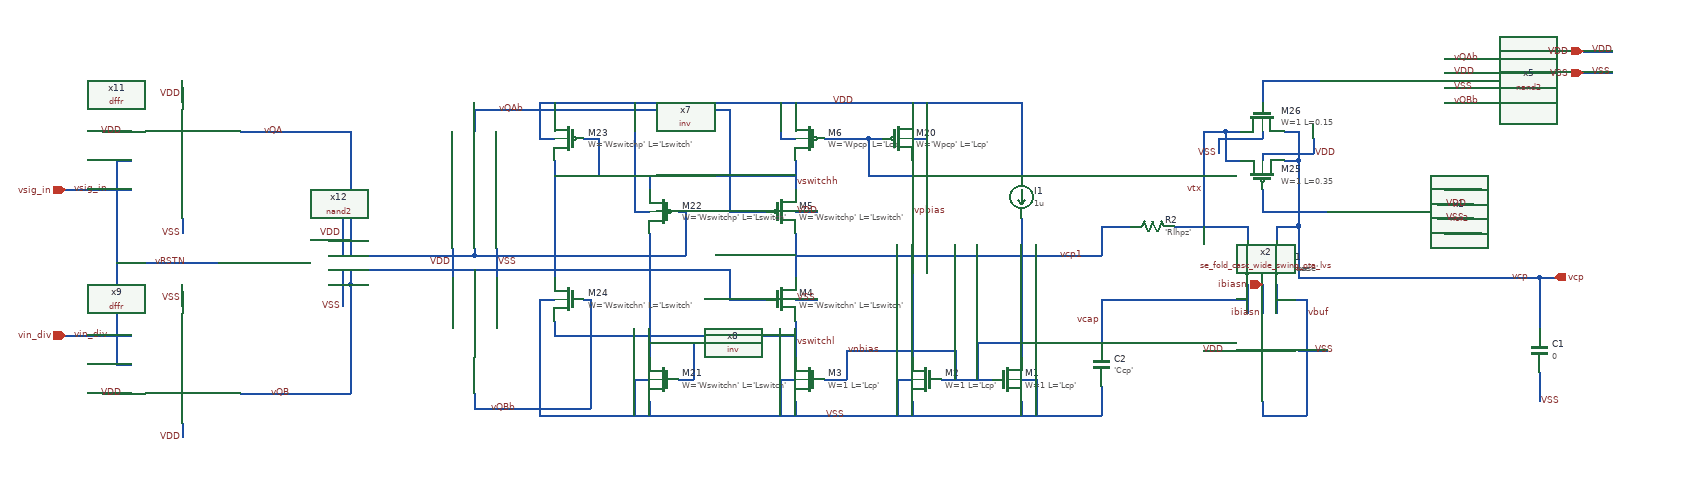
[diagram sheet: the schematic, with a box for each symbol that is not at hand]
v {xschem version=2.9.9 file_version=1.2 }
G {}
K {}
V {}
S {}
E {}
N -1440 -820 -1350 -820 { lab=vin_div}
N -1440 -1020 -1350 -1020 { lab=vsig_in}
N -1080 -890 -1050 -890 { lab=vQB}
N -280 -730 -280 -710 { lab=VSS}
N -300 -760 -280 -760 { lab=VSS}
N -300 -760 -300 -710 { lab=VSS}
N -280 -1090 -260 -1090 { lab=VDD}
N -280 -1140 -280 -1120 { lab=VDD}
N -260 -1140 -260 -1090 { lab=VDD}
N -240 -760 -170 -760 { lab=vnbias}
N -340 -1090 -340 -1040 { lab=vpbias}
N -340 -1040 -280 -1040 { lab=vpbias}
N -340 -1090 -320 -1090 { lab=vpbias}
N -280 -1060 -280 -790 { lab=vpbias}
N -130 -730 -130 -710 { lab=VSS}
N -130 -760 -110 -760 { lab=VSS}
N -110 -760 -110 -710 { lab=VSS}
N -400 -1090 -340 -1090 { lab=vpbias}
N -460 -1090 -440 -1090 { lab=VDD}
N -460 -1140 -460 -1090 { lab=VDD}
N -440 -1140 -440 -1120 { lab=VDD}
N -440 -730 -440 -710 { lab=VSS}
N -460 -760 -440 -760 { lab=VSS}
N -460 -760 -460 -710 { lab=VSS}
N -220 -800 -220 -760 { lab=vnbias}
N -370 -800 -220 -800 { lab=vnbias}
N -370 -800 -370 -760 { lab=vnbias}
N -400 -760 -370 -760 { lab=vnbias}
N -440 -1060 -440 -1020 { lab=vswitchh}
N -440 -960 -440 -900 { lab=vcp1}
N -440 -840 -440 -790 { lab=vswitchl}
N -440 -870 -410 -870 { lab=VSS}
N -440 -990 -410 -990 { lab=VDD}
N -130 -1140 -130 -1040 { lab=VDD}
N -130 -980 -130 -790 { lab=vnbias}
N -190 -810 -190 -760 { lab=vnbias}
N -190 -810 -130 -810 { lab=vnbias}
N 200 -710 260 -710 { lab=vbuf}
N 200 -730 200 -710 { lab=vbuf}
N -20 -750 -20 -710 { lab=VSS}
N 220 -870 260 -870 { lab=vbuf}
N 260 -870 260 -710 { lab=vbuf}
N -20 -870 -20 -810 { lab=vcap}
N 180 -890 180 -850 { lab=vcap}
N 220 -890 220 -850 { lab=vbuf}
N -440 -930 -20 -930 { lab=vcp1}
N 180 -970 180 -950 { lab=vtx}
N 220 -970 220 -950 { lab=vcp}
N -660 -990 -640 -990 { lab=VDD}
N -600 -760 -580 -760 { lab=#net1}
N -580 -810 -580 -760 { lab=#net1}
N -640 -810 -580 -810 { lab=#net1}
N -770 -840 -770 -820 { lab=vswitchl}
N -790 -870 -770 -870 { lab=VSS}
N -790 -1090 -770 -1090 { lab=VDD}
N -790 -1140 -790 -1090 { lab=VDD}
N -770 -1140 -770 -1120 { lab=VDD}
N -660 -760 -640 -760 { lab=VSS}
N -640 -730 -640 -710 { lab=VSS}
N -660 -760 -660 -710 { lab=VSS}
N -730 -1090 -710 -1090 { lab=#net2}
N -710 -1090 -710 -1040 { lab=#net2}
N -770 -1040 -710 -1040 { lab=#net2}
N -640 -1040 -440 -1040 { lab=vswitchh}
N -770 -820 -440 -820 { lab=vswitchl}
N -500 -990 -480 -990 { lab=vQAb}
N -600 -990 -590 -990 { lab=vQA}
N -500 -870 -480 -870 { lab=vQB}
N -730 -870 -720 -870 { lab=vQBb}
N -790 -710 -20 -710 { lab=VSS}
N -790 -1140 -130 -1140 { lab=VDD}
N -530 -990 -500 -990 { lab=vQAb}
N -530 -910 -530 -870 { lab=vQB}
N -530 -870 -500 -870 { lab=vQB}
N -640 -1040 -640 -1020 { lab=vswitchh}
N -640 -960 -640 -790 { lab=#net1}
N -660 -1140 -660 -990 { lab=VDD}
N -790 -870 -790 -710 { lab=VSS}
N -770 -1060 -770 -900 { lab=#net2}
N -20 -870 10 -870 { lab=vcap}
N 150 -1100 150 -1080 { lab=vtx}
N 150 -1100 170 -1100 { lab=vtx}
N 150 -1080 150 -1060 { lab=vtx}
N 150 -1060 170 -1060 { lab=vtx}
N 230 -1100 250 -1100 { lab=vcp}
N 250 -1100 250 -1060 { lab=vcp}
N 230 -1060 250 -1060 { lab=vcp}
N 110 -870 180 -870 { lab=vcap}
N 200 -1020 200 -990 { lab=#net3}
N 200 -1170 200 -1140 { lab=#net4}
N 200 -1070 200 -1060 { lab=VDD}
N 200 -1100 200 -1090 { lab=VSS}
N 200 -1070 270 -1070 { lab=VDD}
N 270 -1090 270 -1070 { lab=VDD}
N 140 -1090 200 -1090 { lab=VSS}
N 140 -1090 140 -1070 { lab=VSS}
N 120 -1100 150 -1100 { lab=vtx}
N 10 -870 110 -870 { lab=vcap}
N -20 -970 -20 -930 { lab=vcp1}
N 220 -970 250 -970 { lab=vcp}
N 200 -1170 280 -1170 { lab=#net4}
N 450 -1200 500 -1200 { lab=vQAb}
N 450 -1140 500 -1140 { lab=vQBb}
N 450 -1020 500 -1020 { lab=vQA}
N 450 -960 500 -960 { lab=vQB}
N 250 -970 250 -900 { lab=vcp}
N 250 -900 580 -900 { lab=vcp}
N -1200 -1100 -1050 -1100 { lab=vQA}
N -1200 -740 -1050 -740 { lab=vQB}
N -1370 -920 -1230 -920 { lab=vRSTN}
N -880 -1130 -880 -1100 { lab=vQAb}
N -880 -740 -880 -720 { lab=vQBb}
N -880 -940 -880 -930 { lab=vQA}
N -880 -910 -880 -900 { lab=vQB}
N -1050 -1100 -1050 -930 { lab=vQA}
N -1050 -930 -880 -930 { lab=vQA}
N -880 -1130 -530 -1130 { lab=vQAb}
N -530 -1130 -530 -990 { lab=vQAb}
N -880 -930 -590 -930 { lab=vQA}
N -590 -990 -590 -930 { lab=vQA}
N -1080 -950 -1050 -950 { lab=vQA}
N -1050 -910 -1050 -890 { lab=vQB}
N -1050 -910 -530 -910 { lab=vQB}
N -880 -720 -720 -720 { lab=vQBb}
N -720 -870 -720 -720 { lab=vQBb}
N -1370 -780 -1350 -780 { lab=vRSTN}
N -1370 -1060 -1370 -780 { lab=vRSTN}
N -1370 -1060 -1350 -1060 { lab=vRSTN}
N -1390 -1100 -1350 -1100 { lab=VDD}
N -1390 -740 -1350 -740 { lab=VDD}
N 580 -900 580 -830 { lab=vcp}
N -20 -970 20 -970 { lab=vcp1}
N 80 -970 180 -970 { lab=vtx}
N 120 -1100 120 -970 { lab=vtx}
N 250 -1060 250 -970 { lab=vcp}
N 200 -990 290 -990 { lab=#net3}
N -1050 -890 -1050 -740 { lab=vQB}
N 200 -890 200 -850 { lab=ibiasn}
N 120 -800 150 -800 { lab=VDD}
N 250 -800 290 -800 { lab=VSS}
N 580 -770 580 -730 { lab=VSS}
N 640 -1180 680 -1180 { lab=VSS}
N 640 -1210 680 -1210 { lab=VDD}
N 580 -900 600 -900 { lab=vcp}
N -910 -940 -910 -900 { lab=VDD}
N -850 -940 -850 -900 { lab=VSS}
N -1280 -1160 -1280 -1140 { lab=VDD}
N -1280 -980 -1280 -960 { lab=VSS}
N -1280 -880 -1280 -860 { lab=VSS}
N -1280 -700 -1280 -680 { lab=VDD}
N -1080 -930 -1060 -930 { lab=VDD}
N -1060 -980 -1060 -930 { lab=VDD}
N -1080 -910 -1060 -910 { lab=VSS}
N -1060 -910 -1060 -860 { lab=VSS}
N 450 -1180 490 -1180 { lab=VDD}
N 490 -1180 500 -1180 { lab=VDD}
N 450 -1160 490 -1160 { lab=VSS}
N 490 -1160 500 -1160 { lab=VSS}
N 440 -1000 480 -1000 { lab=VDD}
N 480 -1000 490 -1000 { lab=VDD}
N 440 -980 480 -980 { lab=#net5}
N 480 -980 490 -980 { lab=#net5}
C {devices/title.sym} 160 -30 0 0 {name=l1 author="Nikhil Poole"}
C {devices/lab_wire.sym} -1380 -1020 0 0 {name=l2 sig_type=std_logic lab=vsig_in}
C {devices/lab_wire.sym} -1380 -820 0 0 {name=l3 sig_type=std_logic lab=vin_div}
C {devices/lab_wire.sym} -370 -800 0 1 {name=l5 sig_type=std_logic lab=vnbias}
C {devices/lab_wire.sym} -280 -990 0 1 {name=l6 sig_type=std_logic lab=vpbias}
C {devices/isource.sym} -130 -1010 0 1 {name=I1 value=1u}
C {sky130_fd_pr/nfet_01v8.sym} -150 -760 0 0 {name=M1
L='Lcp'
W=1
nf=1 
mult=100
ad="'int((nf+1)/2) * W/nf * 0.29'" 
pd="'2*int((nf+1)/2) * (W/nf + 0.29)'"
as="'int((nf+2)/2) * W/nf * 0.29'" 
ps="'2*int((nf+2)/2) * (W/nf + 0.29)'"
nrd="'0.29 / W'" nrs="'0.29 / W'"
sa=0 sb=0 sd=0
model=nfet_01v8
spiceprefix=X
}
C {sky130_fd_pr/nfet_01v8.sym} -260 -760 0 1 {name=M2
L='Lcp'
W=1
nf=1 
mult=1
ad="'int((nf+1)/2) * W/nf * 0.29'" 
pd="'2*int((nf+1)/2) * (W/nf + 0.29)'"
as="'int((nf+2)/2) * W/nf * 0.29'" 
ps="'2*int((nf+2)/2) * (W/nf + 0.29)'"
nrd="'0.29 / W'" nrs="'0.29 / W'"
sa=0 sb=0 sd=0
model=nfet_01v8
spiceprefix=X
}
C {sky130_fd_pr/nfet_01v8.sym} -420 -760 0 1 {name=M3
L='Lcp'
W=1
nf=1 
mult=1
ad="'int((nf+1)/2) * W/nf * 0.29'" 
pd="'2*int((nf+1)/2) * (W/nf + 0.29)'"
as="'int((nf+2)/2) * W/nf * 0.29'" 
ps="'2*int((nf+2)/2) * (W/nf + 0.29)'"
nrd="'0.29 / W'" nrs="'0.29 / W'"
sa=0 sb=0 sd=0
model=nfet_01v8
spiceprefix=X
}
C {sky130_fd_pr/nfet_01v8_lvt.sym} -460 -870 0 0 {name=M4
L='Lswitch'
W='Wswitchn'
nf=1
mult=1
ad="'int((nf+1)/2) * W/nf * 0.29'" 
pd="'2*int((nf+1)/2) * (W/nf + 0.29)'"
as="'int((nf+2)/2) * W/nf * 0.29'" 
ps="'2*int((nf+2)/2) * (W/nf + 0.29)'"
nrd="'0.29 / W'" nrs="'0.29 / W'"
sa=0 sb=0 sd=0
model=nfet_01v8_lvt
spiceprefix=X
}
C {sky130_fd_pr/pfet_01v8_lvt.sym} -460 -990 0 0 {name=M5
L='Lswitch'
W='Wswitchp'
nf=1
mult=1
ad="'int((nf+1)/2) * W/nf * 0.29'" 
pd="'2*int((nf+1)/2) * (W/nf + 0.29)'"
as="'int((nf+2)/2) * W/nf * 0.29'" 
ps="'2*int((nf+2)/2) * (W/nf + 0.29)'"
nrd="'0.29 / W'" nrs="'0.29 / W'"
sa=0 sb=0 sd=0
model=pfet_01v8_lvt
spiceprefix=X
}
C {devices/lab_wire.sym} 540 -900 0 1 {name=l12 sig_type=std_logic lab=vcp}
C {sky130_fd_pr/pfet_01v8.sym} -420 -1090 0 1 {name=M6
L='Lcp'
W='Wpcp'
nf=1
mult='Mpcp'
ad="'int((nf+1)/2) * W/nf * 0.29'" 
pd="'2*int((nf+1)/2) * (W/nf + 0.29)'"
as="'int((nf+2)/2) * W/nf * 0.29'" 
ps="'2*int((nf+2)/2) * (W/nf + 0.29)'"
nrd="'0.29 / W'" nrs="'0.29 / W'"
sa=0 sb=0 sd=0
model=pfet_01v8
spiceprefix=X
}
C {sky130_fd_pr/pfet_01v8.sym} -300 -1090 0 0 {name=M20
L='Lcp'
W='Wpcp'
nf=1
mult='Mpcp'
ad="'int((nf+1)/2) * W/nf * 0.29'" 
pd="'2*int((nf+1)/2) * (W/nf + 0.29)'"
as="'int((nf+2)/2) * W/nf * 0.29'" 
ps="'2*int((nf+2)/2) * (W/nf + 0.29)'"
nrd="'0.29 / W'" nrs="'0.29 / W'"
sa=0 sb=0 sd=0
model=pfet_01v8
spiceprefix=X
}
C {devices/capa.sym} -20 -780 0 0 {name=C2
m=1
value='Ccp'
footprint=1206
device="ceramic capacitor"}
C {devices/res.sym} 220 -920 0 0 {name=R1
value='Rbase'
footprint=1206
device=resistor
m=1}
C {devices/res.sym} 180 -920 0 1 {name=R4
value='Kcap*Rbase'
footprint=1206
device=resistor
m=1}
C {devices/lab_wire.sym} -20 -840 0 0 {name=l35 sig_type=std_logic lab=vcap}
C {devices/lab_wire.sym} 260 -850 2 0 {name=l36 sig_type=std_logic lab=vbuf}
C {devices/lab_wire.sym} -1130 -740 0 0 {name=l37 sig_type=std_logic lab=vQB}
C {devices/lab_wire.sym} -440 -1030 0 1 {name=l38 sig_type=std_logic lab=vswitchh}
C {devices/lab_wire.sym} -440 -810 0 1 {name=l39 sig_type=std_logic lab=vswitchl}
C {sky130_fd_pr/nfet_01v8.sym} -620 -760 0 1 {name=M21
L='Lswitch'
W='Wswitchn'
nf=1 
mult=1
ad="'int((nf+1)/2) * W/nf * 0.29'" 
pd="'2*int((nf+1)/2) * (W/nf + 0.29)'"
as="'int((nf+2)/2) * W/nf * 0.29'" 
ps="'2*int((nf+2)/2) * (W/nf + 0.29)'"
nrd="'0.29 / W'" nrs="'0.29 / W'"
sa=0 sb=0 sd=0
model=nfet_01v8
spiceprefix=X
}
C {sky130_fd_pr/pfet_01v8.sym} -620 -990 0 1 {name=M22
L='Lswitch'
W='Wswitchp'
nf=1
mult=1
ad="'int((nf+1)/2) * W/nf * 0.29'" 
pd="'2*int((nf+1)/2) * (W/nf + 0.29)'"
as="'int((nf+2)/2) * W/nf * 0.29'" 
ps="'2*int((nf+2)/2) * (W/nf + 0.29)'"
nrd="'0.29 / W'" nrs="'0.29 / W'"
sa=0 sb=0 sd=0
model=pfet_01v8
spiceprefix=X
}
C {devices/lab_wire.sym} -1170 -1100 0 1 {name=l40 sig_type=std_logic lab=vQA}
C {sky130_fd_pr/pfet_01v8.sym} -750 -1090 0 1 {name=M23
L='Lswitch'
W='Wswitchp'
nf=1
mult=1
ad="'int((nf+1)/2) * W/nf * 0.29'" 
pd="'2*int((nf+1)/2) * (W/nf + 0.29)'"
as="'int((nf+2)/2) * W/nf * 0.29'" 
ps="'2*int((nf+2)/2) * (W/nf + 0.29)'"
nrd="'0.29 / W'" nrs="'0.29 / W'"
sa=0 sb=0 sd=0
model=pfet_01v8
spiceprefix=X
}
C {sky130_fd_pr/nfet_01v8.sym} -750 -870 0 1 {name=M24
L='Lswitch'
W='Wswitchn'
nf=1 
mult=1
ad="'int((nf+1)/2) * W/nf * 0.29'" 
pd="'2*int((nf+1)/2) * (W/nf + 0.29)'"
as="'int((nf+2)/2) * W/nf * 0.29'" 
ps="'2*int((nf+2)/2) * (W/nf + 0.29)'"
nrd="'0.29 / W'" nrs="'0.29 / W'"
sa=0 sb=0 sd=0
model=nfet_01v8
spiceprefix=X
}
C {devices/lab_wire.sym} -820 -720 0 0 {name=l41 sig_type=std_logic lab=vQBb}
C {sky130_fd_pr/pfet_01v8_lvt.sym} 200 -1040 3 0 {name=M25
L=0.35
W=1
nf=1
mult=1
ad="'int((nf+1)/2) * W/nf * 0.29'" 
pd="'2*int((nf+1)/2) * (W/nf + 0.29)'"
as="'int((nf+2)/2) * W/nf * 0.29'" 
ps="'2*int((nf+2)/2) * (W/nf + 0.29)'"
nrd="'0.29 / W'" nrs="'0.29 / W'"
sa=0 sb=0 sd=0
model=pfet_01v8_lvt
spiceprefix=X
}
C {sky130_fd_pr/nfet_01v8_lvt.sym} 200 -1120 1 0 {name=M26
L=0.15
W=1
nf=1
mult=1
ad="'int((nf+1)/2) * W/nf * 0.29'" 
pd="'2*int((nf+1)/2) * (W/nf + 0.29)'"
as="'int((nf+2)/2) * W/nf * 0.29'" 
ps="'2*int((nf+2)/2) * (W/nf + 0.29)'"
nrd="'0.29 / W'" nrs="'0.29 / W'"
sa=0 sb=0 sd=0
model=nfet_01v8_lvt
spiceprefix=X
}
C {devices/lab_wire.sym} -80 -930 0 1 {name=l44 sig_type=std_logic lab=vcp1}
C {/home/users/nhpoole/ee272b/ee272b_mixed_signal_mmwave_accelerator/designs/nand2.sym} 380 -1170 0 1 {name=x5 M=1}
C {devices/lab_wire.sym} 460 -1200 0 1 {name=l45 sig_type=std_logic lab=vQAb}
C {devices/lab_wire.sym} 460 -1020 0 1 {name=l46 sig_type=std_logic lab=vQA}
C {devices/lab_wire.sym} 460 -960 0 1 {name=l47 sig_type=std_logic lab=vQB}
C {devices/lab_wire.sym} 460 -1140 0 1 {name=l48 sig_type=std_logic lab=vQBb}
C {devices/lab_wire.sym} -1320 -920 0 1 {name=l49 sig_type=std_logic lab=vRSTN}
C {/home/users/nhpoole/ee272b/ee272b_mixed_signal_mmwave_accelerator/designs/inv.sym} -880 -990 3 0 {name=x7 M=1}
C {/home/users/nhpoole/ee272b/ee272b_mixed_signal_mmwave_accelerator/designs/inv.sym} -880 -850 3 1 {name=x8 M=1}
C {devices/lab_wire.sym} -810 -1130 0 0 {name=l50 sig_type=std_logic lab=vQAb}
C {/home/users/nhpoole/ee272b/ee272b_mixed_signal_mmwave_accelerator/designs/dffr.sym} -1280 -780 2 1 {name=x9 M=1}
C {/home/users/nhpoole/ee272b/ee272b_mixed_signal_mmwave_accelerator/designs/dffr.sym} -1280 -1060 0 0 {name=x11 M=1}
C {/home/users/nhpoole/ee272b/ee272b_mixed_signal_mmwave_accelerator/designs/nand2.sym} -1150 -920 0 1 {name=x12 M=1}
C {devices/capa.sym} 580 -800 0 0 {name=C1
m=1
value=0
footprint=1206
device="ceramic capacitor"}
C {devices/res.sym} 50 -970 1 1 {name=R2
value='Rlhpz'
footprint=1206
device=resistor
m=1}
C {/home/users/nhpoole/ee272b/ee272b_mixed_signal_mmwave_accelerator/designs/nor2.sym} 400 -990 0 1 {name=x1 M=1}
C {devices/noconn.sym} -1200 -820 0 1 {name=l11}
C {devices/noconn.sym} -1200 -1020 0 1 {name=l13}
C {devices/lab_wire.sym} 120 -1020 0 0 {name=l14 sig_type=std_logic lab=vtx}
C {devices/lab_wire.sym} -390 -1140 0 1 {name=l8 sig_type=std_logic lab=VDD}
C {devices/lab_wire.sym} -400 -710 0 1 {name=l9 sig_type=std_logic lab=VSS}
C {/home/users/nhpoole/ee272b/ee272b_mixed_signal_mmwave_accelerator/designs/se_fold_casc_wide_swing_ota_lvs.sym} 200 -800 3 1 {name=x2}
C {devices/lab_wire.sym} 200 -850 3 1 {name=l15 sig_type=std_logic lab=ibiasn}
C {devices/lab_wire.sym} 270 -800 0 1 {name=l16 sig_type=std_logic lab=VSS}
C {devices/lab_wire.sym} 150 -800 0 0 {name=l17 sig_type=std_logic lab=VDD}
C {devices/lab_wire.sym} 580 -730 0 1 {name=l4 sig_type=std_logic lab=VSS}
C {devices/lab_wire.sym} 140 -1070 0 0 {name=l18 sig_type=std_logic lab=VSS}
C {devices/lab_wire.sym} 270 -1070 0 1 {name=l19 sig_type=std_logic lab=VDD}
C {devices/lab_wire.sym} -440 -990 0 1 {name=l10 sig_type=std_logic lab=VDD}
C {devices/lab_wire.sym} -440 -870 0 1 {name=l7 sig_type=std_logic lab=VSS}
C {devices/ipin.sym} 640 -1210 0 0 {name=p1 lab=VDD}
C {devices/ipin.sym} 640 -1180 0 0 {name=p2 lab=VSS}
C {devices/lab_wire.sym} 650 -1180 0 1 {name=l20 sig_type=std_logic lab=VSS}
C {devices/lab_wire.sym} 650 -1210 0 1 {name=l21 sig_type=std_logic lab=VDD}
C {devices/lab_wire.sym} -1360 -1100 0 0 {name=l22 sig_type=std_logic lab=VDD}
C {devices/lab_wire.sym} -1360 -740 0 0 {name=l23 sig_type=std_logic lab=VDD}
C {devices/ipin.sym} -1440 -820 0 0 {name=p3 lab=vin_div}
C {devices/ipin.sym} -1440 -1020 0 0 {name=p4 lab=vsig_in}
C {devices/opin.sym} 600 -900 0 0 {name=p5 lab=vcp}
C {devices/ipin.sym} 200 -890 1 0 {name=p6 lab=ibiasn}
C {devices/lab_wire.sym} -850 -920 0 1 {name=l24 sig_type=std_logic lab=VSS}
C {devices/lab_wire.sym} -910 -920 0 0 {name=l25 sig_type=std_logic lab=VDD}
C {devices/lab_wire.sym} -1280 -1150 0 0 {name=l26 sig_type=std_logic lab=VDD}
C {devices/lab_wire.sym} -1280 -960 0 0 {name=l27 sig_type=std_logic lab=VSS}
C {devices/lab_wire.sym} -1280 -870 0 0 {name=l28 sig_type=std_logic lab=VSS}
C {devices/lab_wire.sym} -1280 -680 0 0 {name=l29 sig_type=std_logic lab=VDD}
C {devices/lab_wire.sym} -1060 -960 0 0 {name=l30 sig_type=std_logic lab=VDD}
C {devices/lab_wire.sym} -1060 -860 0 0 {name=l31 sig_type=std_logic lab=VSS}
C {devices/lab_wire.sym} 460 -1180 0 1 {name=l32 sig_type=std_logic lab=VDD}
C {devices/lab_wire.sym} 460 -1160 0 1 {name=l33 sig_type=std_logic lab=VSS}
C {devices/lab_wire.sym} 450 -1000 0 1 {name=l34 sig_type=std_logic lab=VDD}
C {devices/lab_wire.sym} 450 -980 0 1 {name=l42 sig_type=std_logic lab=VSS}
